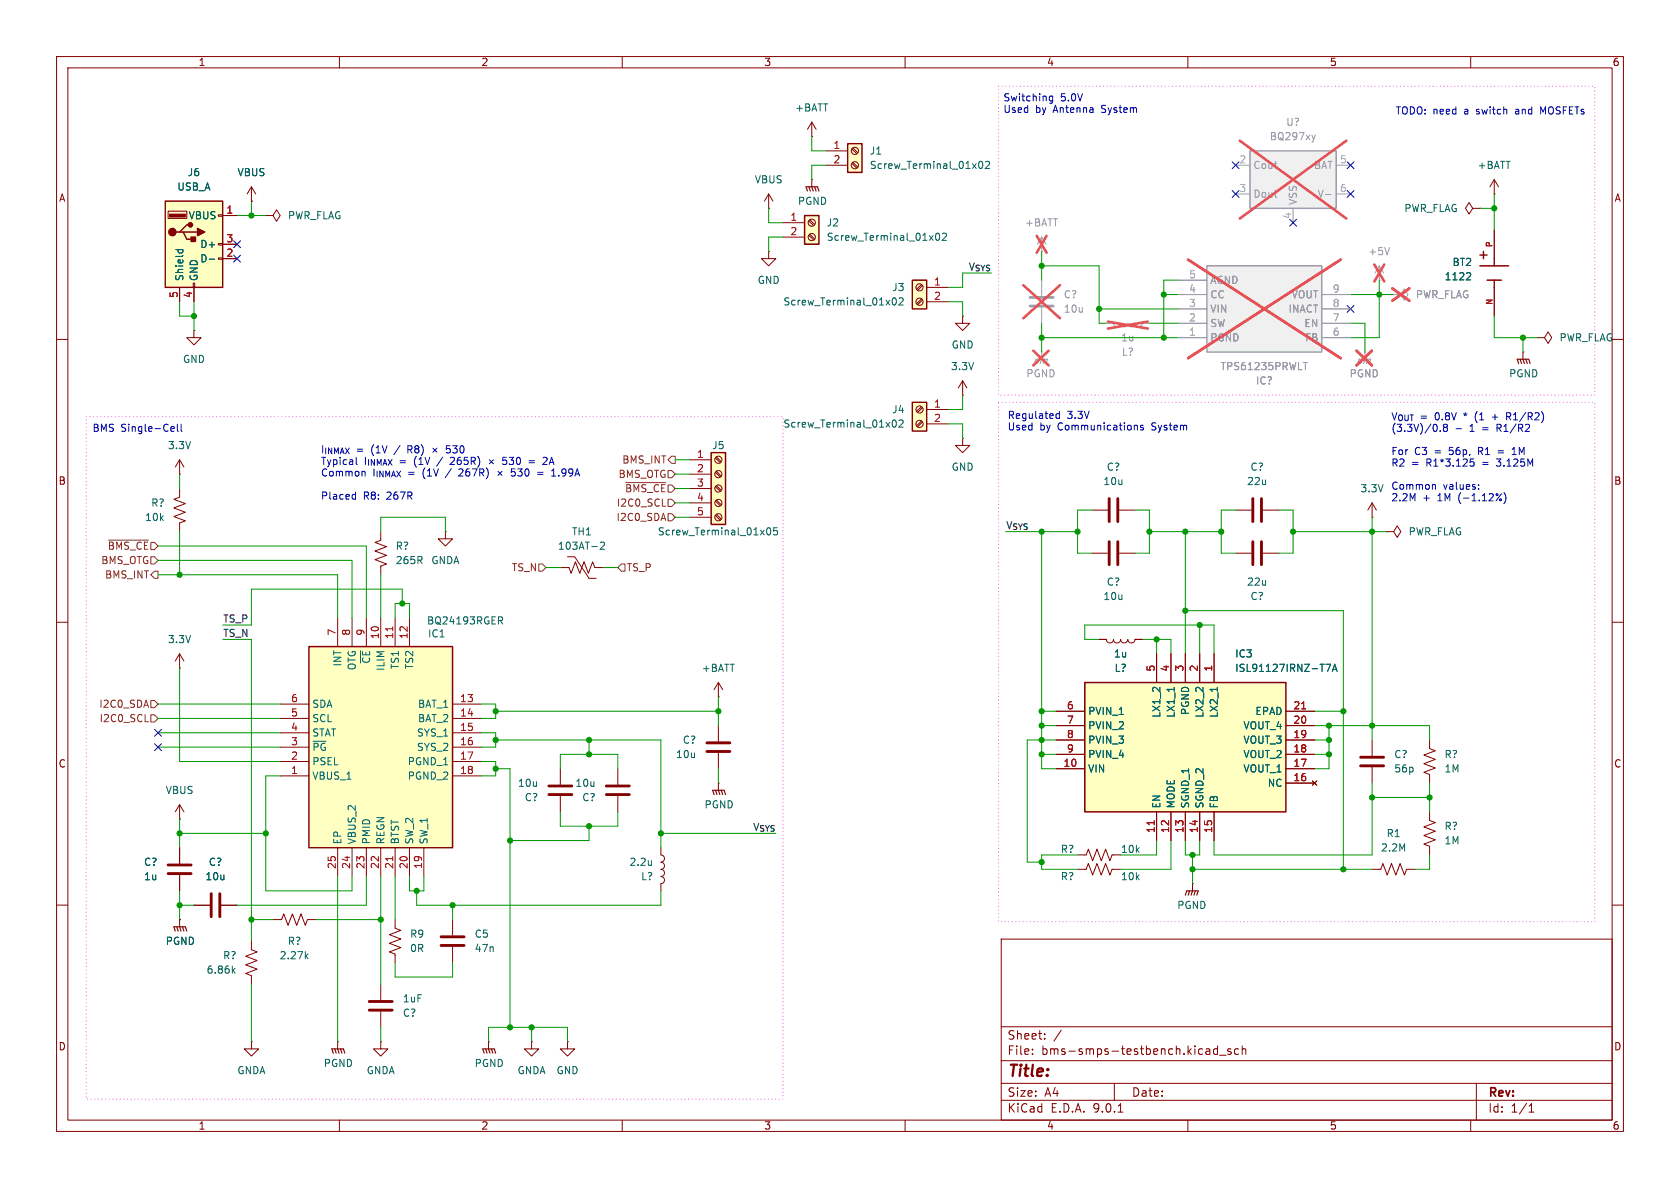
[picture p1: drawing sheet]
<svg xmlns="http://www.w3.org/2000/svg" width="297mm" height="210mm" viewBox="0 0 297 210" stroke-linecap="round" stroke-linejoin="round" font-family="sans-serif">
<defs><g id="words">
<text font-size="2.8" fill="#840000" x="178" y="190.9">Title:</text>
<g font-size="2.1" fill="#840000">
<text x="178" y="184">Sheet:</text>
<text x="178" y="186.7">File:</text>
<text x="184.1" y="186.7">bms-smps-testbench.kicad_sch</text>
<text x="178" y="196.9">KiCad</text>
<text x="178" y="194.1">Size:</text>
<text x="184.7" y="194.1">A4</text>
<text x="185.7" y="196.9">E.D.A.</text>
<text x="193.3" y="196.9">9.0.1</text>
<text x="200" y="194.1">Date:</text>
<text x="263" y="194.3">Rev:</text>
<text x="263" y="196.9">Id:</text>
<text x="267.1" y="196.9">1/1</text>
</g>
<g font-size="1.8" fill="#840000">
<text x="35" y="11.9">1</text>
<text x="85" y="11.9">2</text>
<text x="135" y="11.9">3</text>
<text x="185" y="11.9">4</text>
<text x="235" y="11.9">5</text>
<text x="285" y="11.9">6</text>
<text x="10.3" y="35.9">A</text>
<text x="285.3" y="35.9">A</text>
<text x="10.3" y="85.9">B</text>
<text x="285.3" y="85.9">B</text>
<text x="10.3" y="135.9">C</text>
<text x="285.3" y="135.9">C</text>
<text x="10.3" y="185.9">D</text>
<text x="285.3" y="185.9">D</text>
<text x="35" y="199.9">1</text>
<text x="85" y="199.9">2</text>
<text x="135" y="199.9">3</text>
<text x="185" y="199.9">4</text>
<text x="235" y="199.9">5</text>
<text x="285" y="199.9">6</text>
</g>
<g font-size="1.8" fill="#006464">
<text x="140.5" y="19.9">+BATT</text>
<text x="153.7" y="27.5">J1</text>
<text x="31.3" y="33.9">USB_A</text>
<text x="33.1" y="31.3">J6</text>
<text x="41.9" y="31.3">VBUS</text>
<text x="133.3" y="32.6">VBUS</text>
<text x="153.7" y="30.1">Screw_Terminal_01x02</text>
<text x="261.1" y="30.1">+BATT</text>
<text x="33.3" y="39">VBUS</text>
<text x="50.8" y="39">PWR_FLAG</text>
<text x="141" y="36.4">PGND</text>
<text x="146.1" y="40.2">J2</text>
<text x="248.2" y="37.7">PWR_FLAG</text>
<text x="35.3" y="44">D+</text>
<text x="35.3" y="46.6">D-</text>
<text x="146.1" y="42.8">Screw_Terminal_01x02</text>
<text x="256.7" y="47.2">BT2</text>
<text x="32.6" y="49.8" transform="rotate(-90 32.6 49.8)">Shield</text>
<text x="35.2" y="49.8" transform="rotate(-90 35.2 49.8)">GND</text>
<text x="133.9" y="50.4">GND</text>
<text x="157.6" y="51.7">J3</text>
<text x="255.3" y="49.8">1122</text>
<text x="138.4" y="54.2">Screw_Terminal_01x02</text>
<text x="32.3" y="64.4">GND</text>
<text x="168" y="65.6">3.3V</text>
<text x="168.1" y="61.8">GND</text>
<text x="275.6" y="60.6">PWR_FLAG</text>
<text x="266.7" y="66.9">PGND</text>
<text x="138.4" y="75.8">Screw_Terminal_01x02</text>
<text x="157.6" y="73.3">J4</text>
<text x="29.6" y="79.6">3.3V</text>
<text x="125.8" y="79.6">J5</text>
<text x="168.1" y="83.4">GND</text>
<text x="195.6" y="83.4">C?</text>
<text x="221" y="83.4">C?</text>
<text x="26.6" y="89.8">R?</text>
<text x="195" y="86">10u</text>
<text x="220.4" y="86">22u</text>
<text x="240.4" y="87.2">3.3V</text>
<text x="25.5" y="92.3">10k</text>
<text x="101" y="94.8">TH1</text>
<text x="116.2" y="94.8">Screw_Terminal_01x05</text>
<text x="248.9" y="94.8">PWR_FLAG</text>
<text x="69.9" y="99.9">265R</text>
<text x="69.9" y="97.4">R?</text>
<text x="76.2" y="99.9">GNDA</text>
<text x="98.5" y="97.4">103AT-2</text>
<text x="195" y="106.3">10u</text>
<text x="195.6" y="103.7">C?</text>
<text x="220.4" y="103.7">22u</text>
<text x="221" y="106.3">C?</text>
<text x="29.6" y="113.9">3.3V</text>
<text x="75.4" y="110.6">BQ24193RGER</text>
<text x="75.6" y="112.9">IC1</text>
<text x="60.6" y="117.9" transform="rotate(-90 60.6 117.9)">INT</text>
<text x="63.1" y="118.6" transform="rotate(-90 63.1 118.6)">OTG</text>
<text x="65.6" y="117.4" transform="rotate(-90 65.6 117.4)">~{CE}</text>
<text x="68.2" y="118.7" transform="rotate(-90 68.2 118.7)">ILIM</text>
<text x="70.7" y="118.4" transform="rotate(-90 70.7 118.4)">TS1</text>
<text x="73.3" y="118.4" transform="rotate(-90 73.3 118.4)">TS2</text>
<text x="124" y="119">+BATT</text>
<text x="196.8" y="116.4">1u</text>
<text x="197" y="119">L?</text>
<text x="218.3" y="116.4">IC3</text>
<text x="218.3" y="119">ISL91127IRNZ-T7A</text>
<text x="55.1" y="125.3">SDA</text>
<text x="73.8" y="125.3">BAT_1</text>
<text x="55.1" y="130.4">STAT</text>
<text x="55.1" y="127.9">SCL</text>
<text x="73.6" y="130.4">SYS_1</text>
<text x="73.8" y="127.9">BAT_2</text>
<text x="120.6" y="131.7">C?</text>
<text x="192.3" y="126.6">PVIN_1</text>
<text x="192.3" y="129.1">PVIN_2</text>
<text x="192.3" y="131.7">PVIN_3</text>
<text x="205.3" y="127" transform="rotate(-90 205.3 127)">LX1_2</text>
<text x="207.9" y="127" transform="rotate(-90 207.9 127)">LX1_1</text>
<text x="210.4" y="126.5" transform="rotate(-90 210.4 126.5)">PGND</text>
<text x="213" y="127" transform="rotate(-90 213 127)">LX2_2</text>
<text x="215.5" y="127" transform="rotate(-90 215.5 127)">LX2_1</text>
<text x="219.7" y="129.1">VOUT_4</text>
<text x="219.7" y="131.7">VOUT_3</text>
<text x="221.8" y="126.6">EPAD</text>
<text x="55.1" y="135.5">PSEL</text>
<text x="55.1" y="132.9">~{PG}</text>
<text x="72" y="135.5">PGND_1</text>
<text x="73.6" y="132.9">SYS_2</text>
<text x="119.4" y="134.2">10u</text>
<text x="192.3" y="134.2">PVIN_4</text>
<text x="192.3" y="136.8">VIN</text>
<text x="219.7" y="134.2">VOUT_2</text>
<text x="219.7" y="136.8">VOUT_1</text>
<text x="246.4" y="134.2">C?</text>
<text x="246.4" y="136.8">56p</text>
<text x="255.3" y="136.8">1M</text>
<text x="255.3" y="134.2">R?</text>
<text x="29.2" y="140.6">VBUS</text>
<text x="55.1" y="138">VBUS_1</text>
<text x="72" y="138">PGND_2</text>
<text x="91.5" y="139.3">10u</text>
<text x="92.7" y="141.8">C?</text>
<text x="101.6" y="139.3">10u</text>
<text x="102.8" y="141.8">C?</text>
<text x="124.5" y="143.1">PGND</text>
<text x="205.3" y="143" transform="rotate(-90 205.3 143)">EN</text>
<text x="207.9" y="143" transform="rotate(-90 207.9 143)">MODE</text>
<text x="210.4" y="143" transform="rotate(-90 210.4 143)">SGND_1</text>
<text x="213" y="143" transform="rotate(-90 213 143)">SGND_2</text>
<text x="215.5" y="143" transform="rotate(-90 215.5 143)">FB</text>
<text x="224" y="139.3">NC</text>
<text x="60.6" y="149.4" transform="rotate(-90 60.6 149.4)">EP</text>
<text x="63.1" y="149.4" transform="rotate(-90 63.1 149.4)">VBUS_2</text>
<text x="65.6" y="149.4" transform="rotate(-90 65.6 149.4)">PMID</text>
<text x="68.2" y="149.4" transform="rotate(-90 68.2 149.4)">REGN</text>
<text x="70.7" y="149.4" transform="rotate(-90 70.7 149.4)">BTST</text>
<text x="73.3" y="149.4" transform="rotate(-90 73.3 149.4)">SW_2</text>
<text x="75.8" y="149.4" transform="rotate(-90 75.8 149.4)">SW_1</text>
<text x="245" y="148.2">R1</text>
<text x="255.3" y="149.5">1M</text>
<text x="255.3" y="146.9">R?</text>
<text x="25.4" y="153.3">C?</text>
<text x="25.4" y="155.8">1u</text>
<text x="36.2" y="155.8">10u</text>
<text x="36.8" y="153.3">C?</text>
<text x="111.2" y="153.3">2.2u</text>
<text x="113.2" y="155.8">L?</text>
<text x="187.4" y="155.8">R?</text>
<text x="187.4" y="151">R?</text>
<text x="198.1" y="151">10k</text>
<text x="198.1" y="155.8">10k</text>
<text x="244" y="150.7">2.2M</text>
<text x="208" y="160.9">PGND</text>
<text x="29.2" y="167.2">PGND</text>
<text x="50.8" y="167.2">R?</text>
<text x="72.4" y="166">R9</text>
<text x="83.8" y="166">C5</text>
<text x="36.4" y="172.3">6.86k</text>
<text x="39.3" y="169.8">R?</text>
<text x="49.3" y="169.8">2.27k</text>
<text x="72.4" y="168.5">0R</text>
<text x="83.8" y="168.5">47n</text>
<text x="71.1" y="177.4">1uF</text>
<text x="71.1" y="179.9">C?</text>
<text x="41.9" y="190.1">GNDA</text>
<text x="57.1" y="188.8">PGND</text>
<text x="64.7" y="190.1">GNDA</text>
<text x="83.8" y="188.8">PGND</text>
<text x="91.4" y="190.1">GNDA</text>
<text x="98.3" y="190.1">GND</text>
</g>
<g font-size="1.8" fill="#0000c2">
<text x="177.3" y="18.2">Switching</text>
<text x="177.3" y="20.3">Used</text>
<text x="183.1" y="20.3">by</text>
<text x="186.3" y="20.3">Antenna</text>
<text x="187.5" y="18.2">5.0V</text>
<text x="195" y="20.3">System</text>
<text x="246.6" y="20.3">TODO: need</text>
<text x="259" y="20.3">a</text>
<text x="261.3" y="20.3">switch</text>
<text x="268.4" y="20.3">and</text>
<text x="273" y="20.3">MOSFETs</text>
<text x="16.3" y="76.7">BMS</text>
<text x="21.4" y="76.7">Single-Cell</text>
<text x="178.1" y="74.4">Regulated</text>
<text x="178.1" y="76.4">Used</text>
<text x="183.8" y="76.4">by</text>
<text x="187.1" y="76.4">Communications</text>
<text x="188.7" y="74.4">3.3V</text>
<text x="203.9" y="76.4">System</text>
<text x="245.9" y="74.6">V_{OUT} 0.8V</text>
<text x="245.9" y="76.7">(3.3V)/0.8</text>
<text x="251" y="74.6">=</text>
<text x="259.1" y="74.6">*</text>
<text x="259.9" y="76.7">1</text>
<text x="261.2" y="74.6">(1</text>
<text x="262.3" y="76.7">=</text>
<text x="264.4" y="74.6">+</text>
<text x="265.1" y="76.7">R1/R2</text>
<text x="267.2" y="74.6">R1/R2)</text>
<text x="56.6" y="80.4">I_{INMAX} (1V</text>
<text x="56.6" y="82.4">Typical</text>
<text x="63" y="80.4">=</text>
<text x="64.4" y="82.4">I_{INMAX} (1V</text>
<text x="70" y="80.4">/</text>
<text x="70.7" y="82.4">=</text>
<text x="72.5" y="80.4">R8)</text>
<text x="77.8" y="82.4">/</text>
<text x="80.3" y="82.4">265R)</text>
<text x="97.5" y="82.4">2A</text>
<text x="245.9" y="80.8">For</text>
<text x="245.9" y="82.8">R2</text>
<text x="249.5" y="82.8">=</text>
<text x="250.1" y="80.8">C3</text>
<text x="252.3" y="82.8">R1*3.125</text>
<text x="253.7" y="80.8">=</text>
<text x="256.5" y="80.8">56p,</text>
<text x="261.8" y="80.8">R1</text>
<text x="262.3" y="82.8">=</text>
<text x="265.1" y="82.8">3.125M</text>
<text x="268.2" y="80.8">1M</text>
<text x="56.6" y="84.4">Common</text>
<text x="56.6" y="88.5">Placed</text>
<text x="64.2" y="88.5">R8:</text>
<text x="65.9" y="84.4">I_{INMAX} (1V</text>
<text x="68.5" y="88.5">267R</text>
<text x="72.2" y="84.4">=</text>
<text x="79.3" y="84.4">/</text>
<text x="81.8" y="84.4">267R)</text>
<text x="96.3" y="84.4">=</text>
<text x="99" y="84.4">1.99A</text>
<text x="245.9" y="86.9">Common</text>
<text x="245.9" y="88.9">2.2M</text>
<text x="251.5" y="88.9">+</text>
<text x="254.3" y="88.9">1M</text>
<text x="255.1" y="86.9">values:</text>
<text x="258.1" y="88.9">(-1.12%)</text>
</g>
<g font-size="1.8" fill="#989898">
<text x="227.3" y="22.5">U?</text>
<text x="224.4" y="25">BQ297xy</text>
<text x="221.5" y="30.1">Cout</text>
<text x="221.5" y="35.2">Dout</text>
<text x="232.2" y="30.1">BAT</text>
<text x="232.8" y="35.2">V-</text>
<text x="181.1" y="40.2">+BATT</text>
<text x="229.5" y="36.3" transform="rotate(-90 229.5 36.3)">VSS</text>
<text x="241.8" y="45.3">+5V</text>
<text x="188" y="52.9">C?</text>
<text x="213.9" y="52.9">CC</text>
<text x="213.9" y="50.4">AGND</text>
<text x="228.3" y="52.9">VOUT</text>
<text x="250.2" y="52.9">PWR_FLAG</text>
<text x="188" y="55.5">10u</text>
<text x="213.9" y="58">SW</text>
<text x="213.9" y="55.5">VIN</text>
<text x="227.7" y="55.5">INACT</text>
<text x="230.5" y="58">EN</text>
<text x="198.1" y="60.6">1u</text>
<text x="198.2" y="63.1">L?</text>
<text x="213.9" y="60.6">PGND</text>
<text x="215.7" y="65.6">TPS61235PRWLT</text>
<text x="230.6" y="60.6">FB</text>
<text x="181.4" y="66.9">PGND</text>
<text x="221.9" y="68.2">IC?</text>
<text x="238.5" y="66.9">PGND</text>
</g>
<g font-size="1.8" fill="#a90000">
<text x="147.2" y="26.4">1</text>
<text x="147.2" y="29">2</text>
<text x="39.9" y="37.8">1</text>
<text x="139.6" y="39.1">1</text>
<text x="139.6" y="41.7">2</text>
<text x="39.9" y="42.9">3</text>
<text x="39.9" y="45.5">2</text>
<text x="31.5" y="52.8" transform="rotate(-90 31.5 52.8)">5</text>
<text x="34" y="52.8" transform="rotate(-90 34 52.8)">4</text>
<text x="165" y="50.5">1</text>
<text x="165" y="53.1">2</text>
<text x="165" y="72.1">1</text>
<text x="165" y="74.7">2</text>
<text x="123.1" y="81">1</text>
<text x="123.1" y="83.6">2</text>
<text x="123.1" y="86.1">3</text>
<text x="123.1" y="88.6">4</text>
<text x="123.1" y="91.2">5</text>
<text x="59.4" y="112.5" transform="rotate(-90 59.4 112.5)">7</text>
<text x="62" y="112.5" transform="rotate(-90 62 112.5)">8</text>
<text x="64.5" y="112.5" transform="rotate(-90 64.5 112.5)">9</text>
<text x="67.1" y="113.1" transform="rotate(-90 67.1 113.1)">10</text>
<text x="69.6" y="113.1" transform="rotate(-90 69.6 113.1)">11</text>
<text x="72.1" y="113.1" transform="rotate(-90 72.1 113.1)">12</text>
<text x="204.2" y="118.8" transform="rotate(-90 204.2 118.8)">5</text>
<text x="206.8" y="118.8" transform="rotate(-90 206.8 118.8)">4</text>
<text x="209.3" y="118.8" transform="rotate(-90 209.3 118.8)">3</text>
<text x="211.8" y="118.8" transform="rotate(-90 211.8 118.8)">2</text>
<text x="214.4" y="118.8" transform="rotate(-90 214.4 118.8)">1</text>
<text x="51.4" y="124.2">6</text>
<text x="81.2" y="124.2">13</text>
<text x="188.5" y="125.5">6</text>
<text x="228.6" y="125.5">21</text>
<text x="51.4" y="131.8">3</text>
<text x="51.4" y="129.3">4</text>
<text x="51.4" y="126.7">5</text>
<text x="81.2" y="131.8">16</text>
<text x="81.2" y="129.3">15</text>
<text x="81.2" y="126.7">14</text>
<text x="188.5" y="128">7</text>
<text x="188.5" y="130.6">8</text>
<text x="228.6" y="128">20</text>
<text x="228.6" y="130.6">19</text>
<text x="51.4" y="136.9">1</text>
<text x="51.4" y="134.4">2</text>
<text x="81.2" y="136.9">18</text>
<text x="81.2" y="134.4">17</text>
<text x="187.9" y="135.6">10</text>
<text x="188.5" y="133.1">9</text>
<text x="228.6" y="133.1">18</text>
<text x="228.6" y="135.6">17</text>
<text x="228.6" y="138.2">16</text>
<text x="204.2" y="147.4" transform="rotate(-90 204.2 147.4)">11</text>
<text x="206.8" y="147.4" transform="rotate(-90 206.8 147.4)">12</text>
<text x="209.3" y="147.4" transform="rotate(-90 209.3 147.4)">13</text>
<text x="211.8" y="147.4" transform="rotate(-90 211.8 147.4)">14</text>
<text x="214.4" y="147.4" transform="rotate(-90 214.4 147.4)">15</text>
<text x="59.4" y="153.7" transform="rotate(-90 59.4 153.7)">25</text>
<text x="62" y="153.7" transform="rotate(-90 62 153.7)">24</text>
<text x="64.5" y="153.7" transform="rotate(-90 64.5 153.7)">23</text>
<text x="67.1" y="153.7" transform="rotate(-90 67.1 153.7)">22</text>
<text x="69.6" y="153.7" transform="rotate(-90 69.6 153.7)">21</text>
<text x="72.1" y="153.7" transform="rotate(-90 72.1 153.7)">20</text>
<text x="74.7" y="153.7" transform="rotate(-90 74.7 153.7)">19</text>
</g>
<g font-size="1.8" fill="#aaa">
<text x="219" y="29">2</text>
<text x="236.8" y="29">5</text>
<text x="219" y="34">3</text>
<text x="236.8" y="34">6</text>
<text x="228.3" y="38.8" transform="rotate(-90 228.3 38.8)">4</text>
<text x="210.1" y="51.8">4</text>
<text x="210.1" y="49.3">5</text>
<text x="235.5" y="51.8">9</text>
<text x="210.1" y="59.4">1</text>
<text x="210.1" y="56.9">2</text>
<text x="210.1" y="54.4">3</text>
<text x="235.5" y="59.4">6</text>
<text x="235.5" y="56.9">7</text>
<text x="235.5" y="54.4">8</text>
</g>
<g font-size="1.8" fill="#0f0f0f">
<text x="171.1" y="47.9">V_{SYS}</text>
<text x="39.4" y="110.1">TS_P</text>
<text x="39.4" y="112.7">TS_N</text>
<text x="133" y="147">V_{SYS}</text>
</g>
<g font-size="1.8" fill="#725600">
<text x="109.9" y="82.1">BMS_INT</text>
<text x="108.9" y="89.8">I2C0_SCL</text>
<text x="109.2" y="84.7">BMS_OTG</text>
<text x="110.4" y="87.2">~{BMS_CE}</text>
<text x="108.9" y="92.3">I2C0_SDA</text>
<text x="17.8" y="99.9">BMS_OTG</text>
<text x="19" y="97.4">~{BMS_CE}</text>
<text x="90.4" y="101.2">TS_N</text>
<text x="110.7" y="101.2">TS_P</text>
<text x="18.5" y="102.5">BMS_INT</text>
<text x="17.4" y="125.3">I2C0_SDA</text>
<text x="17.5" y="127.9">I2C0_SCL</text>
</g>
<text font-size="1.8" fill="#009600" x="177.8" y="93.6">V_{SYS}</text>
<g font-size="1.4" fill="#a90000">
<text x="263.9" y="43.8" transform="rotate(-90 263.9 43.8)">P</text>
<text x="263.9" y="54" transform="rotate(-90 263.9 54)">N</text>
</g>
</g></defs>
<g fill="none" stroke="#840000" stroke-width=".18">
<path d="M10 10h277v190h-277zM12 12h273v186h-273zM60 10v2M110 10v2M160 10v2M210 10v2M260 10v2M10 60h2M285 60h2M31.7 86.4v1.5l-1 .4 2.1 .7-2.1 .8 2.1 .8-2.1 .7 2.1 .8-1.1 .4v1.5M10 110h2M285 110h2"/>
<path d="M99.1 135.9v2.8M109.2 135.9v2.8M127 138.4h.1M127 128.3v2.8M127 133.1v2.8M127 138.4v1.3M31.7 144.8h.1M31.7 142.2l.8 1.3M31.7 142.2l-.7 1.3M31.7 142.2v2.6M99.1 140.7v2.8M109.2 140.7v2.8"/>
<path d="M116.8 151.1a.64 .64 0 0 1 .7 .7 .64 .64 0 0 1-.7 .6 .64 .64 0 0 1 .7 .6 .64 .64 0 0 1-.7 .7 .64 .64 0 0 1 .7 .6 .64 .64 0 0 1-.7 .6 .63 .63 0 0 1 .7 .7 .63 .63 0 0 1-.7 .6v1.3M116.8 149.9v1.2M10 160h2M177 166h108v32h-108zM285 160h2M60 198v2M67.3 184.2v1.2h-1.3l1.3 1.3 1.3-1.3h-1.3M67.3 184.2h.1M86.4 184.2h.1M86.4 184.2v1.2M94 184.2v1.2h1.2l-1.2 1.3-1.3-1.3h1.3M94 184.2h.1"/>
<path d="M100.3 184.2v1.2h-1.2l1.2 1.3 1.3-1.3h-1.3M100.3 184.2h.1M110 198v2M160 198v2M177 194.5h108M177 191.5h108M177 187.5h108M177 181.5h108M182.5 186.3v.1M182.5 185.5v.1M184.7 183.6v.1M184.7 182.8v.1"/>
<path d="M187.6 182.1l-1.3 2M197 191.5v3M197.7 196.6h.8M210 198v2M215.2 184.9v1.5M215.2 185.5l-.4-.1-.3 .3v.4l.2 .2h.5M215.6 186.5h1.1M217.6 185.5l-.4-.1-.2 .2 .1 .2 .5 .2v.3h-.6M219 185.5l-.5-.1-.3 .3v.4l.2 .2h.6M219.6 185.5l.2-.1 .4 .1v.9M219.6 184.9v1.5M260 198v2"/>
<path d="M261 191.5v6.5M270.3 196.6h.9M270.3 195.5l.4-.4v1.5"/>
</g>
<path d="M97 138.9h4.1M107.2 138.9h4.1M125 131.3h4M125 132.8h4M97 140.5h4.1M107.2 140.5h4.1" fill="none" stroke="#840000" stroke-width=".51"/>
<path d="M126.5 139.7l.2 .8M127 139.7l.3 .8M127.5 139.7l.3 .8M126.2 140.5l-.2-.8h2l.3 .8M85.6 186.2l-.3-.8h2.1l.2 .8M85.9 185.4l.2 .8M86.4 185.4l.2 .8M86.9 185.4l.2 .8" fill="none" stroke="#840000" stroke-width=".2"/>
<path d="M115.2 152.1v.9M115.2 152.9h-.1" fill="none" stroke="#006464" stroke-width=".18"/>
<path d="M54.6 114.3h25.4v35.6h-25.4z" fill="#ffffc2"/>
<path d="M54.6 114.3h25.4v35.6h-25.4z" fill="none" stroke="#840000" stroke-width=".25"/>
<g fill="none" stroke="#840000" stroke-width=".18">
<path d="M59.7 109.2v5.1M62.2 109.2v5.1M64.8 109.2v5.1M67.3 109.2v5.1M69.8 109.2v5.1M72.4 109.2v5.1M49.5 137.2h5.1M49.5 134.6h5.1M49.5 132.1h5.1M49.5 129.5h5.1M49.5 127h5.1M49.5 124.5h5.1"/>
<path d="M80 137.2h5.1M80 134.6h5.1M80 132.1h5.1M80 129.5h5.1M80 127h5.1M80 124.5h5.1M31.7 149.9v2.8M31.7 154.7v2.8M59.7 149.9v5M62.2 149.9v5M64.8 149.9v5M67.3 149.9v5"/>
<path d="M69.8 149.9v5M72.4 149.9v5M74.9 149.9v5"/>
</g>
<path d="M69.4 110.8v.7M69.4 151.4v.8" fill="none" stroke="#a90000" stroke-width=".18"/>
<path d="M88.1 109h.5l.3 .3-.2 .3-.6 .1M88.4 109.7l.5 .6" fill="none" stroke="#006464" stroke-width=".18"/>
<path d="M29.7 152.9h4.1M29.7 154.4h4.1" fill="none" stroke="#840000" stroke-width=".51"/>
<path d="M125.7 80h2.6v12.7h-2.6z" fill="#ffffc2"/>
<path d="M125.7 80h2.6v12.7h-2.6z" fill="none" stroke="#840000" stroke-width=".25"/>
<g fill="none" stroke="#840000" stroke-width=".18">
<path d="M170.2 69.9h.1M170.2 67.3l.7 1.3M170.2 67.3l-.8 1.3M170.2 67.3v2.6M121.9 81.3h3.8M121.9 83.8h3.8M121.9 86.4h3.8M121.9 88.9h3.8M121.9 91.4h3.8M126.5 80.9l.8 .9M126.5 83.5l.8 .8M126.5 86l.8 .9"/>
<path d="M126.5 88.6l.8 .8M126.5 91.1l.8 .8M126.6 80.8l.9 .8M126.6 83.3l.9 .9M126.6 85.9l.9 .8M126.6 88.4l.9 .8M126.6 90.9l.9 .9M34.3 160h2.8M39.1 160h2.8"/>
<circle cx="127" cy="83.8" r=".63"/>
<circle cx="127" cy="88.9" r=".63"/>
<circle cx="127" cy="86.4" r=".63"/>
<circle cx="127" cy="91.4" r=".63"/>
<circle cx="127" cy="81.3" r=".63"/>
</g>
<path d="M135.6 93.4l.2-.1a.68 .68 0 0 1 .5 .6 .68 .68 0 0 1-.5 .7l-.2-.2-.1-.3zM137.4 93.3h-.6l-.1 .6 .2-.1h.4l.2 .2-.1 .4-.2 .2-.5-.2" fill="none" stroke="#006464" stroke-width=".18"/>
<path d="M37.3 158v4.1M38.9 158v4.1" fill="none" stroke="#840000" stroke-width=".51"/>
<path d="M161.3 49.5h2.5v5.1h-2.5z" fill="#ffffc2"/>
<path d="M161.3 49.5h2.5v5.1h-2.5z" fill="none" stroke="#840000" stroke-width=".25"/>
<g fill="none" stroke="#840000" stroke-width=".18">
<path d="M162.9 50.3l-.8 .8M162.9 52.8l-.8 .9M163.1 50.5l-.9 .8M163.1 53l-.9 .8M163.8 50.8h3.8M163.8 53.3h3.8"/>
<circle cx="162.6" cy="50.8" r=".63"/>
<circle cx="162.6" cy="53.3" r=".63"/>
</g>
<path d="M157.9 52.8l.1-.2a.68 .68 0 0 1 .5 .7 .68 .68 0 0 1-.5 .6l-.1-.1-.2-.4zM158.9 52.8l.5-.2 .3 .4-.8 .9h.8" fill="none" stroke="#006464" stroke-width=".18"/>
<path d="M161.3 71.1h2.5v5.1h-2.5z" fill="#ffffc2"/>
<path d="M161.3 71.1h2.5v5.1h-2.5z" fill="none" stroke="#840000" stroke-width=".25"/>
<g fill="none" stroke="#840000" stroke-width=".18">
<path d="M162.9 71.9l-.8 .8M162.9 74.4l-.8 .9M163.1 72.1l-.9 .8M163.1 74.6l-.9 .8M163.8 72.4h3.8M163.8 74.9h3.8M44.4 166.4v1.5l1.1 .4-2.1 .7 2.1 .8-2.1 .8 2.1 .7-2.1 .8 1 .4v1.5M44.4 184.2v1.2h1.3l-1.3 1.3-1.2-1.3h1.2M44.4 184.2h.1M59.7 184.2h.1M59.7 184.2v1.2"/>
<circle cx="162.6" cy="72.4" r=".63"/>
<circle cx="162.6" cy="74.9" r=".63"/>
</g>
<path d="M157.9 74.4l.1-.2a.68 .68 0 0 1 .5 .7 .68 .68 0 0 1-.5 .6l-.1-.1-.2-.4zM158.9 74.4l.5-.2 .3 .4-.8 .9h.8M41.2 171.5l.4 .5M41.6 171.2l-.5 .5" fill="none" stroke="#006464" stroke-width=".18"/>
<path d="M58.9 186.2l-.2-.8h2l.3 .8M59.2 185.4l.2 .8M59.7 185.4l.2 .8M60.2 185.4l.3 .8" fill="none" stroke="#840000" stroke-width=".2"/>
<path d="M149.9 25.4h2.5v5.1h-2.5z" fill="#ffffc2"/>
<path d="M149.9 25.4h2.5v5.1h-2.5z" fill="none" stroke="#840000" stroke-width=".25"/>
<g fill="none" stroke="#840000" stroke-width=".18">
<path d="M146 26.7h3.9M146 29.2h3.9M150.6 26.3l.9 .9M150.6 28.9l.9 .8M150.8 26.2l.8 .8M150.8 28.7l.8 .8"/>
<circle cx="151.1" cy="26.7" r=".63"/>
<circle cx="151.1" cy="29.2" r=".63"/>
</g>
<path d="M173.1 28.6l.2-.1a.68 .68 0 0 1 .5 .7 .68 .68 0 0 1-.5 .6l-.2-.1-.1-.4zM174.2 28.6l.5-.1 .2 .4-.7 .9h.7" fill="none" stroke="#006464" stroke-width=".18"/>
<path d="M142.2 38.1h2.6v5.1h-2.6z" fill="#ffffc2"/>
<path d="M142.2 38.1h2.6v5.1h-2.6z" fill="none" stroke="#840000" stroke-width=".25"/>
<g fill="none" stroke="#840000" stroke-width=".18">
<path d="M44.4 35.6h.1M44.4 33l.8 1.3M44.4 33l-.7 1.3M44.4 33v2.6M47 38.1h1.3l.6-1 .6 1-.6 1-.6-1M47 38.1h.1M138.4 39.4h3.8M143 39l.8 .9M143.2 38.9l.8 .8M143.5 24.1h.1M143.5 31.8h.1M143.5 21.6l-.8 1.3"/>
<path d="M143.5 21.6l.8 1.3M143.5 21.6v2.5M143.5 31.8v1.2M34.3 58.4v1.3h-1.3l1.3 1.3 1.3-1.3h-1.3M34.3 58.4h.1M138.4 41.9h3.8M143 41.6l.8 .8M143.2 41.4l.8 .8M170.2 55.9v1.3h-1.3l1.3 1.2 1.2-1.2h-1.2M170.2 55.9h.1M31.7 83.8h.1M31.7 81.3v2.5"/>
<path d="M31.7 81.3l.8 1.3M31.7 81.3l-.7 1.3M67.3 94v1.5l-1 .4 2 .7-2 .8 2 .8-2 .7 2 .8-1 .4v1.5M78.7 94v1.3h-1.2l1.2 1.2 1.3-1.2h-1.3M78.7 94h.1M31.7 118.1h.1M31.7 115.6l.8 1.2M31.7 115.6l-.7 1.2M31.7 115.6v2.5"/>
<circle cx="143.5" cy="39.4" r=".63"/>
<circle cx="143.5" cy="41.9" r=".63"/>
</g>
<path d="M165.6 41.3l.1-.1a.68 .68 0 0 1 .4 .7 .68 .68 0 0 1-.4 .6 .84 .84 0 0 1-.1-1.2zM166.6 41.3l.5-.1 .2 .4-.8 .9h.8" fill="none" stroke="#006464" stroke-width=".18"/>
<path d="M142.7 33.8l-.2-.8h2l.3 .8M143 33l.3 .8M143.5 33l.3 .8M144 33l.3 .8" fill="none" stroke="#840000" stroke-width=".2"/>
<path d="M182.9 64.3l.2-.8h2.1l-.3 .8M183.6 63.5l-.2 .8M184.1 63.5l-.2 .8M184.7 63.5l-.3 .8" fill="none" stroke="#a1a1a1" stroke-width=".2"/>
<path d="M184.1 49.5v2.8M184.1 54.4v2.8M184.1 62.2h.1M184.1 62.2v1.3" fill="none" stroke="#a1a1a1" stroke-width=".18"/>
<path d="M180.9 50.4l6.5 5.9M187.4 50.4l-6.5 5.9M182.7 62l2.7 2.6M185.4 62l-2.7 2.6" fill="none" stroke="#e65255" stroke-width=".46"/>
<path d="M182.1 52.6h4.1M182.1 54.1h4.1" fill="none" stroke="#a1a1a1" stroke-width=".51"/>
<path d="M29.2 35.6h10.2v15.2h-10.2z" fill="#ffffc2"/>
<path d="M29.2 35.6h10.2v15.2h-10.2zM33.7 39.8h-.7l-1.3 1.2h-.6M31.7 41h.7l.6 1.3h1.3M32.4 41h2.5" fill="none" stroke="#840000" stroke-width=".25"/>
<g fill="#840000" stroke="#840000" stroke-width=".25">
<path d="M33.8 41.9h.7v.8h-.7z"/>
<path d="M34.9 40.4l1.3 .6-1.3 .7z"/>
<circle cx="30.5" cy="41" r=".63"/>
<circle cx="33.7" cy="39.8" r=".38"/>
</g>
<path d="M30 37.8h2.8v.6h-2.8z" fill="#840000" stroke="#840000" stroke-width=".18"/>
<g fill="none" stroke="#840000" stroke-width=".18">
<path d="M29.7 37.3h3.3v1.3h-3.3zM38.6 38h.8v.2h-.8zM39.4 38.1h2.5M135.9 36.8h.1M135.9 34.3l.8 1.3M135.9 34.3l-.8 1.3M135.9 34.3v2.5M31.7 50.8v2.5M34.2 50h.2v.8h-.2zM34.3 50.8v2.5M38.6 43.1h.8v.2h-.8zM38.6 45.6h.8v.2h-.8z"/>
<path d="M39.4 43.2h2.5M39.4 45.7h2.5M135.9 44.5v1.2h-1.3l1.3 1.3 1.3-1.3h-1.3M135.9 44.5h.1M170.2 77.5v1.2h-1.3l1.3 1.3 1.2-1.3h-1.2M170.2 77.5h.1M100.3 98.4h1.3l2.5 3.8h1.3M193 90.2h2.8M197.9 90.2h2.8M218.4 90.2h2.8M223.3 90.2h2.8M242.6 91.4h.1"/>
<path d="M242.6 88.9l.7 1.3M242.6 88.9l-.8 1.3M242.6 88.9v2.5M99.1 100.3h1.5l.4 1 .7-2 .8 2 .8-2 .7 2 .8-2 .4 1h1.5M127 123.2h.1M127 120.7l-.8 1.2M127 120.7l.8 1.2M127 120.7v2.5M31.7 162.6h.1M31.7 162.6v1.2"/>
</g>
<path d="M31.1 44.1h1.2M31.5 44.1v.4M32.3 44.1v.4M37 45.8h1M106.1 96l.5-.2 .3 .4-.8 .9h.8" fill="none" stroke="#006464" stroke-width=".18"/>
<path d="M196.1 88.1v4.1M197.6 88.1v4.1M221.5 88.1v4.1M223 88.1v4.1" fill="none" stroke="#840000" stroke-width=".51"/>
<path d="M31 164.6l-.3-.8h2.1l.2 .8M31.2 163.8l.3 .8M31.7 163.8l.3 .8M32.3 163.8l.2 .8" fill="none" stroke="#840000" stroke-width=".2"/>
<path d="M195.6 57.2h1.2a.64 .64 0 0 0 .7 .6 .64 .64 0 0 0 .6-.6 .64 .64 0 0 0 .7 .6 .64 .64 0 0 0 .6-.6 .64 .64 0 0 0 .6 .6 .64 .64 0 0 0 .7-.6 .64 .64 0 0 0 .6 .6 .64 .64 0 0 0 .6-.6h1.3" fill="none" stroke="#a1a1a1" stroke-width=".18"/>
<path d="M195.9 56.9l7 1.2M202.9 56.9l-7 1.2" fill="none" stroke="#e65255" stroke-width=".46"/>
<path d="M213.4 47h20.3v15.2h-20.3z" fill="#f0f0f0"/>
<path d="M213.4 47h20.3v15.2h-20.3z" fill="none" stroke="#a1a1a1" stroke-width=".25"/>
<g fill="none" stroke="#a1a1a1" stroke-width=".18">
<path d="M184.1 44.5h.1M184.1 41.9l.8 1.3M184.1 41.9l-.7 1.3M184.1 41.9v2.6M208.3 59.7h5.1M208.3 57.2h5.1M208.3 54.6h5.1M208.3 52.1h5.1M208.3 49.5h5.1M233.7 59.7h5.1M233.7 57.2h5.1M233.7 54.6h5.1"/>
<path d="M233.7 52.1h5.1"/>
</g>
<path d="M230.4 64.1h.7" fill="none" stroke="#989898" stroke-width=".18"/>
<path d="M183.3 41.7l1.7 3M185 41.7l-1.7 3M210 45.9l27 17.4M237 45.9l-27 17.4" fill="none" stroke="#e65255" stroke-width=".46"/>
<path d="M221 26.7h15.2v10.1h-15.2z" fill="#f0f0f0"/>
<path d="M221 26.7h15.2v10.1h-15.2z" fill="none" stroke="#a1a1a1" stroke-width=".25"/>
<g fill="none" stroke="#a1a1a1" stroke-width=".18">
<path d="M218.4 29.2h2.6M218.4 34.3h2.6M228.6 36.8v2.6M236.2 29.2h2.6M236.2 34.3h2.6M243.8 49.5h.1M243.8 47l-.7 1.3M243.8 47l.8 1.3M243.8 47v2.5M246.4 52.1h1.2l.7-1 .6 1-.6 1-.7-1M246.4 52.1h.1M241.3 62.2h.1"/>
<path d="M241.3 62.2v1.3"/>
</g>
<path d="M232.5 23.9l-.3 .8M234.3 34.4h1M245.7 43.8l-.5 1.2" fill="none" stroke="#989898" stroke-width=".18"/>
<path d="M219.2 24.9l18.8 13.7M238 24.9l-18.8 13.7M243 46.8l1.7 3M244.7 46.8l-1.7 3M246.2 51l2.9 2.2M249.1 51l-2.9 2.2M239.8 62l2.7 2.6M242.5 62l-2.7 2.6" fill="none" stroke="#e65255" stroke-width=".46"/>
<g fill="none" stroke="#840000" stroke-width=".18">
<path d="M260.3 36.8l-.6 1-.6-1 .6-1 .6 1h1.3M261.6 36.8h.1M264.2 34.3h.1M264.2 31.8l.7 1.2M264.2 31.8l-.8 1.2M264.2 31.8v2.5M264.2 40.6v5.1M264.2 50.8v5.1M271.8 59.7h1.2l.7 1 .6-1-.6-1-.7 1M271.8 59.7h.1M269.2 62.2h.1M269.2 62.2v1.3"/>
<path d="M193 97.8h2.8M197.9 97.8h2.8M218.4 97.8h2.8M223.3 97.8h2.8M245.1 94h1.3l.6 1 .6-1-.6-1-.6 1M245.1 94h.1M194.3 113h1.3a.64 .64 0 0 0 .6 .7 .64 .64 0 0 0 .6-.7 .64 .64 0 0 0 .7 .7 .64 .64 0 0 0 .6-.7 .64 .64 0 0 0 .7 .7 .64 .64 0 0 0 .6-.7 .64 .64 0 0 0 .6 .7 .64 .64 0 0 0 .7-.7h1.2M242.6 130.8v2.8M242.6 135.6v2.8M252.7 130.8v1.5l1 .4-2 .8 2 .7-2 .8 2 .8-2 .7 1 .4v1.5M80 162.6v2.8M80 167.4v2.8"/>
</g>
<path d="M268.5 64.3l-.3-.8h2.1l.2 .8M268.7 63.5l.3 .8M269.2 63.5l.3 .8M269.7 63.5l.3 .8" fill="none" stroke="#840000" stroke-width=".2"/>
<path d="M261.6 45.1h1.3M261.6 47h5.1M262.3 44.5v1.2M262.9 49.5h2.5M264.2 45.7v1.3M264.2 49.5v1.3" fill="none" stroke="#840000" stroke-width=".25"/>
<path d="M259.8 48.2l.2 .2-.1 .3-.7 .8h.8" fill="none" stroke="#006464" stroke-width=".18"/>
<path d="M240 64.3l.3-.8h2l-.2 .8M240.8 63.5l-.3 .8M241.3 63.5l-.3 .8M241.8 63.5l-.2 .8" fill="none" stroke="#a1a1a1" stroke-width=".2"/>
<path d="M196.1 95.8v4M197.6 95.8v4M221.5 95.8v4M223 95.8v4M240.5 133.9h4.1M240.5 135.4h4.1M78 167.1h4M78 165.6h4" fill="none" stroke="#840000" stroke-width=".51"/>
<path d="M191.8 120.7h35.5v22.8h-35.5z" fill="#ffffc2"/>
<path d="M191.8 120.7h35.5v22.8h-35.5z" fill="none" stroke="#840000" stroke-width=".25"/>
<g fill="none" stroke="#840000" stroke-width=".18">
<path d="M39.4 38.1h2.5M44.4 35.6h.1M31.7 50.8v2.5M34.3 50.8v2.5M39.4 43.2h2.5M39.4 45.7h2.5M264.2 40.6v5.1M264.2 50.8v5.1M194.3 113h1.3M200.7 113h1.2M204.5 115.6v5.1M207 115.6v5.1"/>
<path d="M209.5 115.6v5.1M212.1 115.6v5.1M214.6 115.6v5.1M186.7 125.7h5.1M186.7 128.3h5.1M186.7 130.8h5.1M186.7 133.4h5.1M186.7 135.9h5.1M227.3 125.7h5.1M227.3 128.3h5.1M227.3 130.8h5.1M227.3 133.4h5.1"/>
<path d="M227.3 135.9h5.1M227.3 138.4h5.1M232 138l.8 .8M232.8 138l-.8 .8M31.7 149.9v2.8M31.7 154.7v2.8M190.5 153.7h1.5l.4-1 .8 2 .7-2 .8 2 .8-2 .7 2 .4-1h1.5M190.5 151.1h1.5l.4-1 .8 2 .7-2 .8 2 .8-2 .7 2 .4-1h1.5M204.5 143.5v5.1M207 143.5v5.1M209.5 143.5v5.1M210.8 156.2h.1"/>
<path d="M210.8 156.2v1.3M212.1 143.5v5.1M214.6 143.5v5.1M242.6 153.7h1.5l.4-1 .7 2 .8-2 .8 2 .7-2 .8 2 .4-1h1.5M252.7 143.5v1.5l1 .4-2 .8 2 .7-2 .8 2 .8-2 .7 1 .4v1.5M31.7 162.6h.1M34.3 160h2.8M39.1 160h2.8M48.3 162.6h1.5l.4-1.1 .7 2.1 .8-2.1 .8 2.1 .7-2.1 .8 2.1 .4-1h1.5M67.3 174v2.8M67.3 178.8v2.8M69.8 162.6v1.5l1.1 .4-2.1 .7 2.1 .8-2.1 .8 2.1 .7-2.1 .8 1 .4v1.5"/>
</g>
<path d="M31.1 44.1h1.2M31.5 44.1v.4M32.3 44.1v.4M37 45.8h1M259.8 48.2l.2 .2-.1 .3-.7 .8h.8M234.4 117.4h.8l-.5 1.3M235.5 118.7l.5-1.3 .4 1.3M235.7 118.3h.6M207.6 121.5v.7M215.2 121.5v.7M54.1 169l.4 .5M54.5 168.6l-.5 .5" fill="none" stroke="#006464" stroke-width=".18"/>
<path d="M230.1 125.3h.7M204.1 145.1v.7" fill="none" stroke="#a90000" stroke-width=".18"/>
<path d="M209.5 158.2l.3-.7h2l-.2 .7M210.3 157.5l-.2 .7M210.8 157.5l-.2 .7M211.3 157.5l-.2 .7" fill="none" stroke="#840000" stroke-width=".2"/>
<path d="M65.3 178.6h4M65.3 177h4" fill="none" stroke="#840000" stroke-width=".51"/>
<g fill="none" stroke="#725600" stroke-width=".18">
<path d="M19.2 95.5h7.1M26.7 98.4h.6l.6 .7-.6 .6h-.6zM95.2 99.7h.7l.6 .6-.6 .7h-.7zM109.9 99.7h.6v1.3h-.6l-.7-.7zM110.6 85.3h7.1M117.1 89.5h.6M118.1 88.3h.6l.7 .6-.7 .6h-.6zM118.1 81.3l.6-.7h.7v1.3h-.7zM118.1 90.8h.6l.7 .6-.7 .7h-.6zM118.1 83.2h.6l.7 .6-.7 .7h-.6zM27.3 101h.6v1.2h-.6l-.6-.6zM25.7 127.6h.6"/>
<path d="M26.7 123.8h.6l.6 .7-.6 .6h-.6zM26.7 126.4h.6l.6 .6-.6 .6h-.6z"/>
</g>
<g fill="none" stroke="#009600" stroke-width=".18">
<path d="M41.9 38.1h5.1M44.4 35.6v2.5M135.9 36.8v2.6h2.5M143.5 24.1v2.6h2.5M146 29.2h-2.5v2.6M261.6 36.8h2.6M264.2 34.3v6.3M31.7 53.3v2.6h2.6M34.3 53.3v5.1M138.4 41.9h-2.5v2.6M167.6 53.3h2.6v2.6M175.3 48.3h-5.1v2.5h-2.6"/>
<path d="M184.1 44.5v5M184.1 57.2v5M184.1 59.7h24.2M184.1 47h10.2v10.2h1.3M194.3 54.6h14M203.2 57.2h5.1M205.7 52.1h2.6M208.3 49.5h-2.6v10.2M238.8 52.1h7.6M238.8 57.2h2.5v5M243.8 49.5v10.2h-5M264.2 55.9v3.8h7.6"/>
<path d="M269.2 59.7v2.5M167.6 74.9h2.6v2.6M170.2 69.9v2.5h-2.6M27.9 99.1h34.3v10.1M27.9 96.5h36.9v12.7M31.7 83.8v2.6M31.7 94v7.6M67.3 94v-2.6h11.4v2.6M119.4 81.3h2.5M119.4 91.4h2.5M119.4 88.9h2.5M119.4 83.8h2.5"/>
<path d="M119.4 86.4h2.5M177.8 94h12.7M184.1 94v41.9h2.6M193 90.2h-2.5v7.6h2.5M200.7 90.2h2.5v7.6h-2.5M203.2 94h12.7M209.5 94v21.6M218.4 90.2h-2.5v7.6h2.5M226.1 90.2h2.5v7.6h-2.5M228.6 94h16.5M242.6 91.4v39.4M27.9 101.6h31.8v7.6"/>
<path d="M31.7 118.1v16.5h17.8M39.4 113h5v53.4M67.3 101.6v7.6M69.8 109.2v-2.5h2.6v2.5M71.1 106.7v-2.6h-26.7v6.4h-5M96.5 100.3h2.6M106.7 100.3h2.5M194.3 113h-2.5v-2.5h22.8v5.1M201.9 113h5.1v2.6M204.5 113v2.6M209.5 108h28v45.7M212.1 110.5v5.1"/>
<path d="M27.9 129.5h21.6M27.9 127h21.6M27.9 124.5h21.6M27.9 132.1h21.6M49.5 137.2h-2.5v20.3h15.2v-2.6M85.1 124.5h2.5v2.5h-2.5M85.1 129.5h2.5v2.6h-2.5M85.1 134.6h2.5v2.6h-2.5M87.6 130.8h29.2v19.1M87.6 135.9h2.6v45.7M87.6 125.7h39.4M99.1 135.9v-2.5h10.1v2.5"/>
<path d="M104.1 130.8v2.6M127 123.2v5.1M127 135.9v2.5M184.1 133.4h2.6M184.1 125.7h2.6M184.1 128.3h2.6M186.7 130.8h-5.1v21.6h2.5M232.4 130.8h2.5M232.4 133.4h2.5M232.4 125.7h5.1M232.4 128.3h20.3v2.5M234.9 128.3v7.6h-2.5"/>
<path d="M242.6 138.4v12.7h-28v-2.5M252.7 138.4v5.1M31.7 144.8v5.1M31.7 157.5v5.1M31.7 147.3h15.3M59.7 154.9v29.3M64.8 154.9v5.1h-22.9M67.3 154.9v19.1M69.8 154.9v7.7M72.4 154.9v2.6h2.5v-2.6M73.7 157.5v2.5h43.1v-2.5M99.1 143.5v2.6h10.1v-2.6"/>
<path d="M104.1 146.1v2.5h-13.9M116.8 147.3h20.4M190.5 151.1h-6.4v2.6h6.4M204.5 148.6v2.5h-6.4M207 148.6v5.1h-8.9M209.5 148.6v2.5h2.6v-2.5M210.8 151.1v5.1M210.8 153.7h31.8M242.6 141h10.1M252.7 151.1v2.6h-2.5M31.7 160h2.6M44.4 174v10.2"/>
<path d="M44.4 162.6h3.9M55.9 162.6h11.4M69.8 170.2v2.5h10.2v-2.5M80 160v2.6M67.3 181.6v2.6M86.4 184.2v-2.6h13.9v2.6M94 181.6v2.6"/>
</g>
<g fill="none" stroke="#000084" stroke-width=".18">
<path d="M217.8 28.6l1.2 1.2M217.8 33.7l1.2 1.2M219 28.6l-1.2 1.2M219 33.7l-1.2 1.2M228 38.8l1.2 1.2M229.2 38.8l-1.2 1.2M238.2 33.7l1.2 1.2M238.2 28.6l1.2 1.2M239.4 28.6l-1.2 1.2M239.4 33.7l-1.2 1.2M41.3 42.6l1.2 1.2M41.3 45.1l1.2 1.2"/>
<path d="M42.5 42.6l-1.2 1.2M42.5 45.1l-1.2 1.2M238.2 54l1.2 1.2M239.4 54l-1.2 1.2M27.3 128.9l1.2 1.2M27.3 131.5l1.2 1.2M28.5 128.9l-1.2 1.2M28.5 131.5l-1.2 1.2"/>
</g>
<g fill="none" stroke="#0000c2" stroke-width=".18">
<path d="M186.1 17v1l-.2 .3-.3-.1M186.1 17.1l-.4-.1-.2 .2 .1 .6h.5M272.8 19.8l-.4-.9v1.3M30.4 75.4l.3 .1 .1 .2-.6 .1M30.7 76.2l-.3 .1M31.4 75v1.1l.1 .2M32 75v1.1l.2 .2M76.5 79.2l.8 .7M77.3 79.2l-.8 .7M79.6 78.8h-.7v.6l.2-.1h.4l.1 .2v.4l-.2 .2-.5-.2M80 78.8h.8l-.4 .5 .4 .1v.5l-.2 .2-.6-.2M81.5 78.9l.1-.1a.68 .68 0 0 1 .5 .6 .68 .68 0 0 1-.5 .7 .84 .84 0 0 1-.1-1.2z"/>
<path d="M187.3 72.7v1.3M187.3 73.2l-.4-.1-.2 .3 .1 .5h.5M200.7 75.2l.4 .1v.7M202.1 75.2h-.3l-.2 .1 .1 .2 .4 .2v.3h-.5M254.6 76.1v.2M255.4 75.5l-.2 .3v.3l.2 .2 .4-.1 .1-.2v-.2l-.3-.3M257.4 75.8h1M263.8 73.7h1M264.8 79.7h1M266.4 73.6h.4M266.7 73.6l.4 .6M266.8 73h-.4v1.2"/>
<path d="M267.3 79.5l.4-.4v1.3M62.5 87.4l.4 .1M62.9 87v1.2M62.9 88.2h-.4M63 80.8v1.1l.2 .2M64.5 83.4v.8M79.8 80.8l-.2 .2M80.3 81.4l-.7 .7h.7M81.8 83.4l-.7 .8h.8M86.5 81.3l.7 .7M87.2 81.3l-.7 .7M88 83.3l.7 .7"/>
<path d="M88.7 83.3l-.7 .7M89.5 80.8h-.6v.6l.1-.1 .5 .1 .1 .2-.1 .4-.1 .1-.5-.1M90 80.8h.8l-.4 .5 .3 .1v.6l-.1 .1-.6-.1M91 82.9h-.6v.6l.2-.1h.4l.1 .2-.1 .4-.1 .2-.5-.2M91.4 81l.2-.2a.68 .68 0 0 1 .4 .7 .68 .68 0 0 1-.4 .6l-.2-.1-.1-.4zM91.5 82.9h.8l-.4 .5 .4 .1v.5l-.2 .2-.6-.2M92.9 83l.2-.1a.68 .68 0 0 1 .4 .6 .68 .68 0 0 1-.4 .7l-.2-.2-.1-.3zM93.5 81.4h1M93.5 81.8h1M95 83.5h1M95 83.9h1M96 81l.5-.2 .2 .4-.8 .9h.8"/>
<path d="M97.5 84.2h.7M97.6 83.2l.3-.3v1.3M253.4 85.6l.4 .2v.7M259.9 81.1h.6M260.4 81.6l.2 .3v.3l-.2 .2h-.3M261.4 86.4v.1M261.4 85.7v.1M264.8 80.1h1M265.3 88.2l.1 .2-.1 .1M265.4 87.3l-.9 1.2M265.9 87.1a1.46 1.46 0 0 1 0 1.9M267.3 80.4h.7"/>
</g>
<path d="M176.5 15.2h105.4v54.7h-105.4zM15.2 73.7h123.2v120.6h-123.2zM176.5 71.1h105.4v91.8h-105.4z" fill="none" stroke="#f0f" stroke-width=".18" stroke-dasharray="0 .6"/>
<path d="M208.3 59.7h5.1M208.3 57.2h5.1M208.3 54.6h5.1M208.3 52.1h5.1M208.3 49.5h5.1M233.7 59.7h5.1M233.7 57.2h5.1M233.7 54.6h5.1M233.7 52.1h5.1M246.4 52.1h.1M241.3 62.2h.1" fill="none" stroke="#a1a1a1" stroke-width=".18"/>
<path d="M210 45.9l27 17.4M237 45.9l-27 17.4M246.2 51l2.9 2.2M249.1 51l-2.9 2.2M239.8 62l2.7 2.6M242.5 62l-2.7 2.6" fill="none" stroke="#e65255" stroke-width=".46"/>
<path d="M230.4 64.1h.7" fill="none" stroke="#989898" stroke-width=".18"/>
<g fill="#009600" stroke="#009600" stroke-width=".18">
<circle cx="234.9" cy="128.3" r=".46"/>
<circle cx="237.5" cy="125.7" r=".46"/>
<circle cx="234.9" cy="130.8" r=".46"/>
<circle cx="228.6" cy="94" r=".46"/>
<circle cx="242.6" cy="94" r=".46"/>
<circle cx="264.2" cy="36.8" r=".46"/>
<circle cx="243.8" cy="52.1" r=".46"/>
<circle cx="269.2" cy="59.7" r=".46"/>
<circle cx="215.9" cy="94" r=".46"/>
<circle cx="209.5" cy="94" r=".46"/>
<circle cx="204.5" cy="113" r=".46"/>
<circle cx="190.5" cy="94" r=".46"/>
<circle cx="203.2" cy="94" r=".46"/>
<circle cx="209.5" cy="108" r=".46"/>
<circle cx="212.1" cy="110.5" r=".46"/>
<circle cx="184.1" cy="47" r=".46"/>
<circle cx="184.1" cy="59.7" r=".46"/>
<circle cx="184.1" cy="130.8" r=".46"/>
<circle cx="184.1" cy="128.3" r=".46"/>
<circle cx="210.8" cy="153.7" r=".46"/>
<circle cx="210.8" cy="151.1" r=".46"/>
<circle cx="184.1" cy="133.4" r=".46"/>
<circle cx="234.9" cy="133.4" r=".46"/>
<circle cx="252.7" cy="141" r=".46"/>
<circle cx="242.6" cy="141" r=".46"/>
<circle cx="242.6" cy="128.3" r=".46"/>
<circle cx="237.5" cy="153.7" r=".46"/>
<circle cx="205.7" cy="52.1" r=".46"/>
<circle cx="205.7" cy="59.7" r=".46"/>
<circle cx="194.3" cy="54.6" r=".46"/>
<circle cx="34.3" cy="55.9" r=".46"/>
<circle cx="44.4" cy="38.1" r=".46"/>
<circle cx="87.6" cy="125.7" r=".46"/>
<circle cx="71.1" cy="106.7" r=".46"/>
<circle cx="184.1" cy="125.7" r=".46"/>
<circle cx="184.1" cy="152.4" r=".46"/>
<circle cx="127" cy="125.7" r=".46"/>
<circle cx="31.7" cy="101.6" r=".46"/>
<circle cx="104.1" cy="133.4" r=".46"/>
<circle cx="87.6" cy="135.9" r=".46"/>
<circle cx="87.6" cy="130.8" r=".46"/>
<circle cx="90.2" cy="148.6" r=".46"/>
<circle cx="104.1" cy="146.1" r=".46"/>
<circle cx="116.8" cy="147.3" r=".46"/>
<circle cx="104.1" cy="130.8" r=".46"/>
<circle cx="80" cy="160" r=".46"/>
<circle cx="94" cy="181.6" r=".46"/>
<circle cx="90.2" cy="181.6" r=".46"/>
<circle cx="73.7" cy="157.5" r=".46"/>
<circle cx="67.3" cy="162.6" r=".46"/>
<circle cx="31.7" cy="160" r=".46"/>
<circle cx="31.7" cy="147.3" r=".46"/>
<circle cx="44.4" cy="162.6" r=".46"/>
<circle cx="47" cy="147.3" r=".46"/>
</g>
<use href="#words"/>
</svg>
